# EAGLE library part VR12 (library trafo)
TRANSFORMER 1 primary winding, 2 secondary windings BLOCK

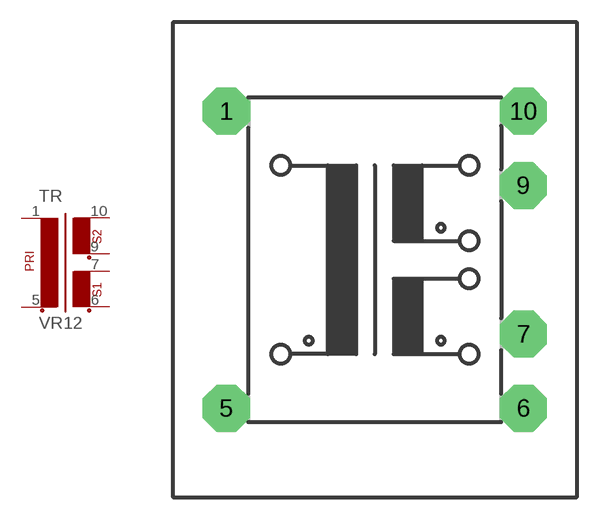
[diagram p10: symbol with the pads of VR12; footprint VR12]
Designator prefix TR

## VR12  [VR12]
1  1  pas
5  2  pas
6  3  pas
7  4  pas
9  5  pas
10  6  pas

## Footprint VR12 (pad centres in mm)
TRANSFORMER 1 primary winding, 2 secondary windings
drill 1.397 pad 3.175 octagon: 1 -10.008,10.008; 5 -10.008,-10.008; 6 10.008,-10.008; 7 10.008,-5.004; 9 10.008,5.004; 10 10.008,10.008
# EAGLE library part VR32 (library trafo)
TRANSFORMER 1 primary winding, 2 secondary windings BLOCK

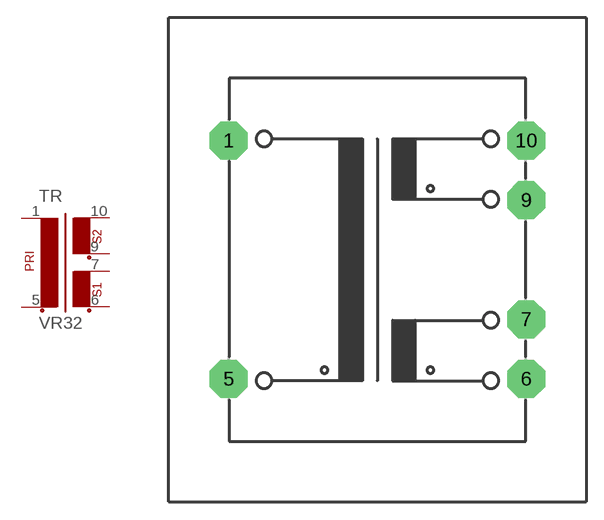
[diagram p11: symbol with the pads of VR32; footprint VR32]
Designator prefix TR

## VR32  [VR32]
1  1  pas
5  2  pas
6  3  pas
7  4  pas
9  5  pas
10  6  pas

## Footprint VR32 (pad centres in mm)
TRANSFORMER 1 primary winding, 2 secondary windings
drill 1.397 pad 3.175 octagon: 1 -12.497,10.008; 5 -12.497,-10.008; 6 12.497,-10.008; 7 12.497,-5.004; 9 12.497,5.004; 10 12.497,10.008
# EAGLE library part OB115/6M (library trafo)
TRANSFORMER 2 primary winding, 2 secondary windings with tap, mounting holes BLOCK

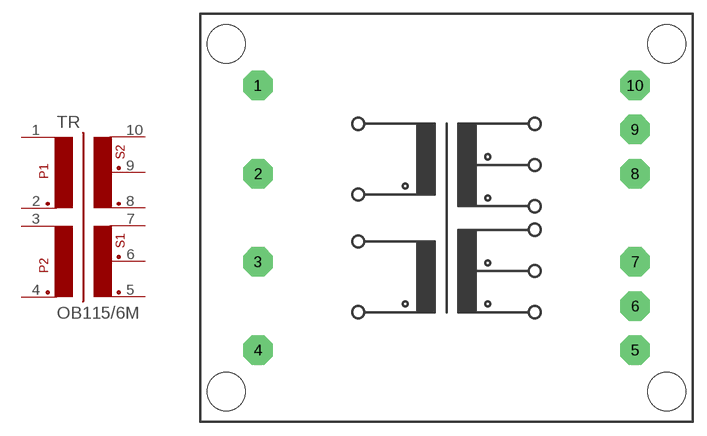
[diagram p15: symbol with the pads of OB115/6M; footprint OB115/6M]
Designator prefix TR

## OB115/6M  [OB115/6M]
1  1  pas
2  2  pas
3  3  pas
4  4  pas
5  5  pas
6  6  pas
7  7  pas
8  8  pas
9  9  pas
10  10  pas

## Footprint OB115/6M (pad centres in mm)
TRANSFORMER 2 primary winding, 2 secondary windings with tap, mounting holes
drill 1.194 pad 3.175 octagon: 1 -20.32,14.275; 2 -20.32,4.75; 3 -20.32,-4.75; 4 -20.32,-14.275; 5 20.32,-14.275; 6 20.32,-9.525; 7 20.32,-4.75; 8 20.32,4.75; 9 20.32,9.525; 10 20.32,14.275
hole 4.115 at 23.749,18.745
hole 4.115 at 23.749,-18.745
hole 4.115 at -23.749,-18.745
hole 4.115 at -23.749,18.745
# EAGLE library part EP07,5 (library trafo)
TRANSFORMER 1 primary winding, 2 secondary windings BLOCK

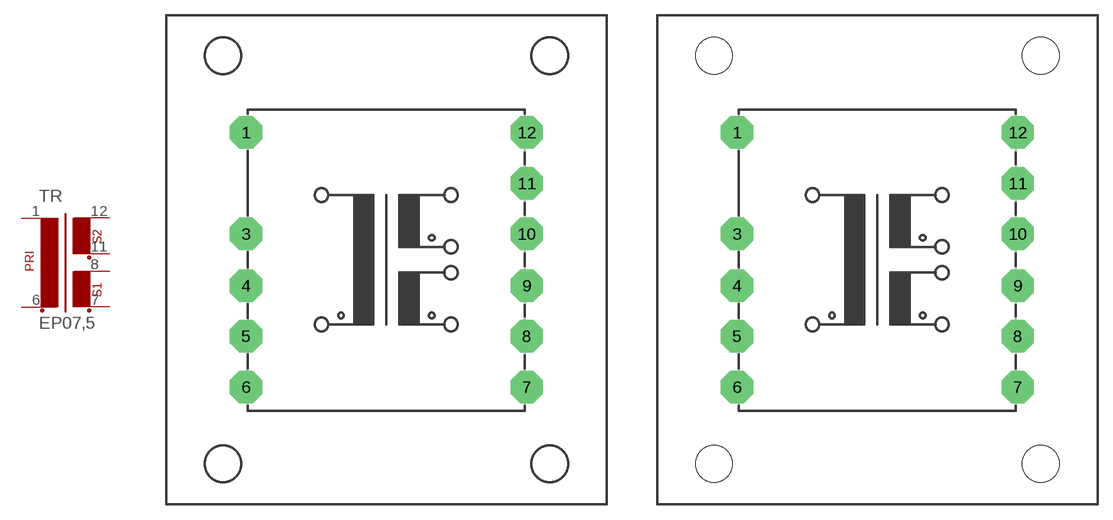
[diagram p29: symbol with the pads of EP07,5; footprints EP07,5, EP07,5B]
Designator prefix TR

## EP07,5  [EP07,5]
1  1  pas
6  2  pas
7  3  pas
8  4  pas
11  5  pas
12  6  pas

## EP07,5MH  [EP07,5B]
Pads as for EP07,5

## Footprint EP07,5 (pad centres in mm)
TRANSFORMER 1 primary winding, 2 secondary windings
drill 1.118 pad 3.175 octagon: 1 -13.767,12.497; 3 -13.767,2.54; 4 -13.767,-2.54; 5 -13.767,-7.493; 6 -13.767,-12.497; 7 13.767,-12.497; 8 13.767,-7.493; 9 13.767,-2.54; 10 13.767,2.54; 11 13.767,7.493; 12 13.767,12.497

## Footprint EP07,5B (pad centres in mm)
TRANSFORMER 1 primary winding, 2 secondary windings, mounting holes
drill 1.118 pad 3.175 octagon: 1 -13.767,12.497; 3 -13.767,2.54; 4 -13.767,-2.54; 5 -13.767,-7.493; 6 -13.767,-12.497; 7 13.767,-12.497; 8 13.767,-7.493; 9 13.767,-2.54; 10 13.767,2.54; 11 13.767,7.493; 12 13.767,12.497
hole 3.607 at -16.027,20.041
hole 3.607 at -16.027,-20.041
hole 3.607 at 16.027,20.041
hole 3.607 at 16.027,-20.041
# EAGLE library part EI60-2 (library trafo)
TRANSFORMER 1 primary winding, 2 secondary windings, mounting holes ERA

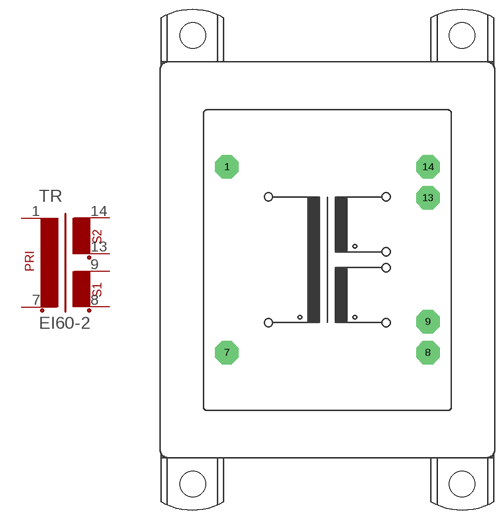
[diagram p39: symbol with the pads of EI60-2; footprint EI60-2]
Designator prefix TR

## EI60-2  [EI60-2]
1  1  pas
7  2  pas
8  3  pas
9  4  pas
13  5  pas
14  6  pas

## Footprint EI60-2 (pad centres in mm)
TRANSFORMER 1 primary winding, 2 secondary windings, mounting holes
drill 1.194 pad 3.81 octagon: 1 -16.256,15.011; 7 -16.256,-15.011; 8 16.256,-15.011; 9 16.256,-10.008; 13 16.256,10.008; 14 16.256,15.011
hole 4.115 at -21.742,-36.246
hole 4.115 at -21.742,36.246
hole 4.115 at 21.742,-36.246
hole 4.115 at 21.742,36.246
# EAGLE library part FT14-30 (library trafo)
TRANSFORMER 2 primary winding, 2 secondary windings, mounting holes ERA

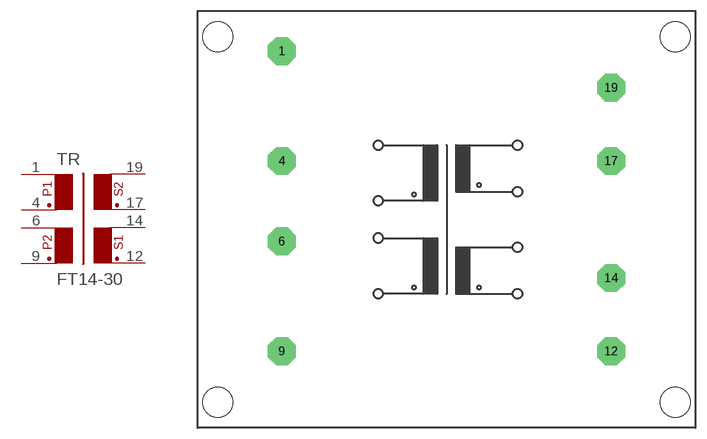
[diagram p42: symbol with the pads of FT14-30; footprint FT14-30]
Designator prefix TR

## FT14-30  [FT14-30]
1  1  pas
4  2  pas
6  3  pas
9  4  pas
12  5  pas
14  6  pas
17  7  pas
19  8  pas

## Footprint FT14-30 (pad centres in mm)
TRANSFORMER 2 primary winding, 2 secondary windings, mounting holes
drill 1.194 pad 3.81 octagon: 1 -22.504,23.012; 4 -22.504,8.001; 6 -22.504,-2.997; 9 -22.504,-18.009; 12 22.504,-18.009; 14 22.504,-8.001; 17 22.504,8.001; 19 22.504,18.009
hole 4.115 at -31.267,24.994
hole 4.115 at 31.267,24.994
hole 4.115 at 31.267,-24.994
hole 4.115 at -31.267,-24.994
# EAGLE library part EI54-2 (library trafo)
TRANSFORMER 1 primary winding, 2 secondary windings ERA

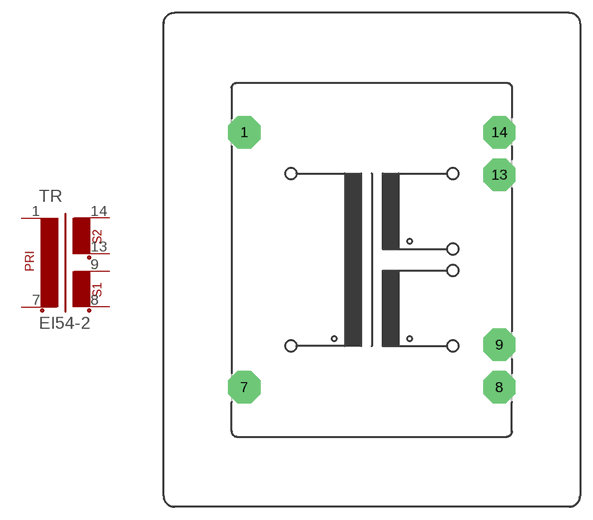
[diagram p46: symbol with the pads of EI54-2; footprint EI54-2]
Designator prefix TR

## EI54-2  [EI54-2]
1  1  pas
7  2  pas
8  3  pas
9  4  pas
13  5  pas
14  6  pas

## Footprint EI54-2 (pad centres in mm)
TRANSFORMER 1 primary winding, 2 secondary windings
drill 1.194 pad 3.81 octagon: 1 -15.011,15.011; 7 -15.011,-15.011; 8 15.011,-15.011; 9 15.011,-10.008; 13 15.011,10.008; 14 15.011,15.011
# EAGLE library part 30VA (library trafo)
TRANSFORMER 1 primary windig + 1 primary winding with tap, 2 secondary windings, core ring

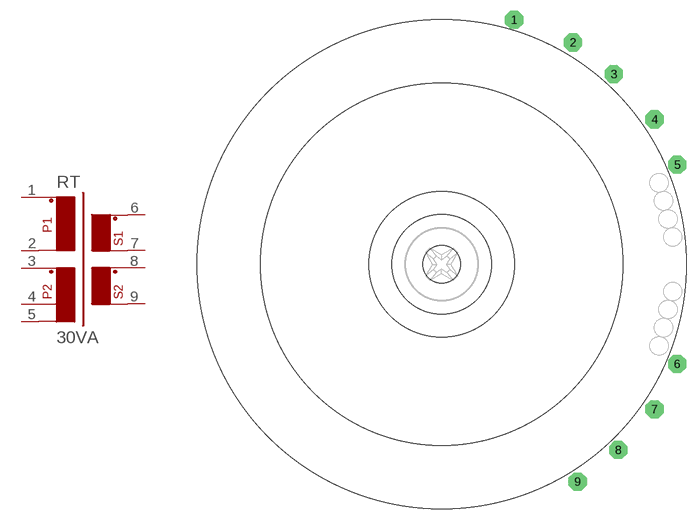
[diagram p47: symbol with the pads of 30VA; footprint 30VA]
Designator prefix RT

## 30VA  [30VA]
1  1  pas
2  2  pas
3  3  pas
4  4  pas
5  5  pas
6  6  pas
7  7  pas
8  8  pas
9  9  pas

## Footprint 30VA (pad centres in mm)
TRANSFORMER 1 primary windig + 1 primary winding with tap, 2 secondary windings, core ring
drill 1.016 pad 2.54 octagon: 1 10.16,34.29; 2 18.415,31.115; 3 24.13,26.67; 4 29.845,20.32; 5 33.02,13.97; 6 33.02,-13.97; 7 29.845,-20.32; 8 24.765,-26.035; 9 19.05,-30.48
hole 5.309 at 0,0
